VERSION 5.7 ;
BUSBITCHARS "[]" ;
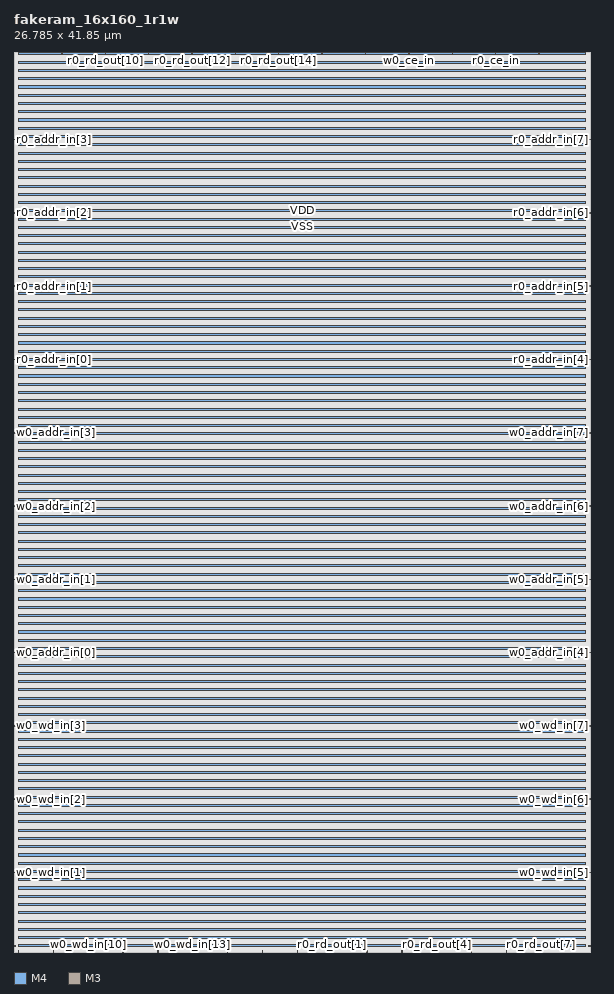
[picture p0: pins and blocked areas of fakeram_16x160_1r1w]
MACRO fakeram_16x160_1r1w
  FOREIGN fakeram_16x160_1r1w 0 0 ;
  SYMMETRY X Y R90 ;
  SIZE 26.785 BY 41.850 ;
  CLASS BLOCK ;
  PIN w0_wd_in[0]
    DIRECTION INPUT ;
    USE SIGNAL ;
    SHAPE ABUTMENT ;
    PORT
      LAYER M4 ;
      RECT 0.000 0.276 0.072 0.300 ;
    END
  END w0_wd_in[0]
  PIN w0_wd_in[1]
    DIRECTION INPUT ;
    USE SIGNAL ;
    SHAPE ABUTMENT ;
    PORT
      LAYER M4 ;
      RECT 0.000 3.684 0.072 3.708 ;
    END
  END w0_wd_in[1]
  PIN w0_wd_in[2]
    DIRECTION INPUT ;
    USE SIGNAL ;
    SHAPE ABUTMENT ;
    PORT
      LAYER M4 ;
      RECT 0.000 7.092 0.072 7.116 ;
    END
  END w0_wd_in[2]
  PIN w0_wd_in[3]
    DIRECTION INPUT ;
    USE SIGNAL ;
    SHAPE ABUTMENT ;
    PORT
      LAYER M4 ;
      RECT 0.000 10.500 0.072 10.524 ;
    END
  END w0_wd_in[3]
  PIN w0_wd_in[4]
    DIRECTION INPUT ;
    USE SIGNAL ;
    SHAPE ABUTMENT ;
    PORT
      LAYER M4 ;
      RECT 26.713 0.276 26.785 0.300 ;
    END
  END w0_wd_in[4]
  PIN w0_wd_in[5]
    DIRECTION INPUT ;
    USE SIGNAL ;
    SHAPE ABUTMENT ;
    PORT
      LAYER M4 ;
      RECT 26.713 3.684 26.785 3.708 ;
    END
  END w0_wd_in[5]
  PIN w0_wd_in[6]
    DIRECTION INPUT ;
    USE SIGNAL ;
    SHAPE ABUTMENT ;
    PORT
      LAYER M4 ;
      RECT 26.713 7.092 26.785 7.116 ;
    END
  END w0_wd_in[6]
  PIN w0_wd_in[7]
    DIRECTION INPUT ;
    USE SIGNAL ;
    SHAPE ABUTMENT ;
    PORT
      LAYER M4 ;
      RECT 26.713 10.500 26.785 10.524 ;
    END
  END w0_wd_in[7]
  PIN w0_wd_in[8]
    DIRECTION INPUT ;
    USE SIGNAL ;
    SHAPE ABUTMENT ;
    PORT
      LAYER M3 ;
      RECT 0.207 0.000 0.225 0.054 ;
    END
  END w0_wd_in[8]
  PIN w0_wd_in[9]
    DIRECTION INPUT ;
    USE SIGNAL ;
    SHAPE ABUTMENT ;
    PORT
      LAYER M3 ;
      RECT 1.827 0.000 1.845 0.054 ;
    END
  END w0_wd_in[9]
  PIN w0_wd_in[10]
    DIRECTION INPUT ;
    USE SIGNAL ;
    SHAPE ABUTMENT ;
    PORT
      LAYER M3 ;
      RECT 3.447 0.000 3.465 0.054 ;
    END
  END w0_wd_in[10]
  PIN w0_wd_in[11]
    DIRECTION INPUT ;
    USE SIGNAL ;
    SHAPE ABUTMENT ;
    PORT
      LAYER M3 ;
      RECT 5.067 0.000 5.085 0.054 ;
    END
  END w0_wd_in[11]
  PIN w0_wd_in[12]
    DIRECTION INPUT ;
    USE SIGNAL ;
    SHAPE ABUTMENT ;
    PORT
      LAYER M3 ;
      RECT 6.687 0.000 6.705 0.054 ;
    END
  END w0_wd_in[12]
  PIN w0_wd_in[13]
    DIRECTION INPUT ;
    USE SIGNAL ;
    SHAPE ABUTMENT ;
    PORT
      LAYER M3 ;
      RECT 8.307 0.000 8.325 0.054 ;
    END
  END w0_wd_in[13]
  PIN w0_wd_in[14]
    DIRECTION INPUT ;
    USE SIGNAL ;
    SHAPE ABUTMENT ;
    PORT
      LAYER M3 ;
      RECT 9.927 0.000 9.945 0.054 ;
    END
  END w0_wd_in[14]
  PIN w0_wd_in[15]
    DIRECTION INPUT ;
    USE SIGNAL ;
    SHAPE ABUTMENT ;
    PORT
      LAYER M3 ;
      RECT 11.547 0.000 11.565 0.054 ;
    END
  END w0_wd_in[15]
  PIN r0_rd_out[0]
    DIRECTION OUTPUT ;
    USE SIGNAL ;
    SHAPE ABUTMENT ;
    PORT
      LAYER M3 ;
      RECT 13.167 0.000 13.185 0.054 ;
    END
  END r0_rd_out[0]
  PIN r0_rd_out[1]
    DIRECTION OUTPUT ;
    USE SIGNAL ;
    SHAPE ABUTMENT ;
    PORT
      LAYER M3 ;
      RECT 14.787 0.000 14.805 0.054 ;
    END
  END r0_rd_out[1]
  PIN r0_rd_out[2]
    DIRECTION OUTPUT ;
    USE SIGNAL ;
    SHAPE ABUTMENT ;
    PORT
      LAYER M3 ;
      RECT 16.407 0.000 16.425 0.054 ;
    END
  END r0_rd_out[2]
  PIN r0_rd_out[3]
    DIRECTION OUTPUT ;
    USE SIGNAL ;
    SHAPE ABUTMENT ;
    PORT
      LAYER M3 ;
      RECT 18.027 0.000 18.045 0.054 ;
    END
  END r0_rd_out[3]
  PIN r0_rd_out[4]
    DIRECTION OUTPUT ;
    USE SIGNAL ;
    SHAPE ABUTMENT ;
    PORT
      LAYER M3 ;
      RECT 19.647 0.000 19.665 0.054 ;
    END
  END r0_rd_out[4]
  PIN r0_rd_out[5]
    DIRECTION OUTPUT ;
    USE SIGNAL ;
    SHAPE ABUTMENT ;
    PORT
      LAYER M3 ;
      RECT 21.267 0.000 21.285 0.054 ;
    END
  END r0_rd_out[5]
  PIN r0_rd_out[6]
    DIRECTION OUTPUT ;
    USE SIGNAL ;
    SHAPE ABUTMENT ;
    PORT
      LAYER M3 ;
      RECT 22.887 0.000 22.905 0.054 ;
    END
  END r0_rd_out[6]
  PIN r0_rd_out[7]
    DIRECTION OUTPUT ;
    USE SIGNAL ;
    SHAPE ABUTMENT ;
    PORT
      LAYER M3 ;
      RECT 24.507 0.000 24.525 0.054 ;
    END
  END r0_rd_out[7]
  PIN r0_rd_out[8]
    DIRECTION OUTPUT ;
    USE SIGNAL ;
    SHAPE ABUTMENT ;
    PORT
      LAYER M3 ;
      RECT 0.207 41.796 0.225 41.850 ;
    END
  END r0_rd_out[8]
  PIN r0_rd_out[9]
    DIRECTION OUTPUT ;
    USE SIGNAL ;
    SHAPE ABUTMENT ;
    PORT
      LAYER M3 ;
      RECT 2.223 41.796 2.241 41.850 ;
    END
  END r0_rd_out[9]
  PIN r0_rd_out[10]
    DIRECTION OUTPUT ;
    USE SIGNAL ;
    SHAPE ABUTMENT ;
    PORT
      LAYER M3 ;
      RECT 4.239 41.796 4.257 41.850 ;
    END
  END r0_rd_out[10]
  PIN r0_rd_out[11]
    DIRECTION OUTPUT ;
    USE SIGNAL ;
    SHAPE ABUTMENT ;
    PORT
      LAYER M3 ;
      RECT 6.255 41.796 6.273 41.850 ;
    END
  END r0_rd_out[11]
  PIN r0_rd_out[12]
    DIRECTION OUTPUT ;
    USE SIGNAL ;
    SHAPE ABUTMENT ;
    PORT
      LAYER M3 ;
      RECT 8.271 41.796 8.289 41.850 ;
    END
  END r0_rd_out[12]
  PIN r0_rd_out[13]
    DIRECTION OUTPUT ;
    USE SIGNAL ;
    SHAPE ABUTMENT ;
    PORT
      LAYER M3 ;
      RECT 10.287 41.796 10.305 41.850 ;
    END
  END r0_rd_out[13]
  PIN r0_rd_out[14]
    DIRECTION OUTPUT ;
    USE SIGNAL ;
    SHAPE ABUTMENT ;
    PORT
      LAYER M3 ;
      RECT 12.303 41.796 12.321 41.850 ;
    END
  END r0_rd_out[14]
  PIN r0_rd_out[15]
    DIRECTION OUTPUT ;
    USE SIGNAL ;
    SHAPE ABUTMENT ;
    PORT
      LAYER M3 ;
      RECT 14.319 41.796 14.337 41.850 ;
    END
  END r0_rd_out[15]
  PIN w0_addr_in[0]
    DIRECTION INPUT ;
    USE SIGNAL ;
    SHAPE ABUTMENT ;
    PORT
      LAYER M4 ;
      RECT 0.000 13.908 0.072 13.932 ;
    END
  END w0_addr_in[0]
  PIN w0_addr_in[1]
    DIRECTION INPUT ;
    USE SIGNAL ;
    SHAPE ABUTMENT ;
    PORT
      LAYER M4 ;
      RECT 0.000 17.316 0.072 17.340 ;
    END
  END w0_addr_in[1]
  PIN w0_addr_in[2]
    DIRECTION INPUT ;
    USE SIGNAL ;
    SHAPE ABUTMENT ;
    PORT
      LAYER M4 ;
      RECT 0.000 20.724 0.072 20.748 ;
    END
  END w0_addr_in[2]
  PIN w0_addr_in[3]
    DIRECTION INPUT ;
    USE SIGNAL ;
    SHAPE ABUTMENT ;
    PORT
      LAYER M4 ;
      RECT 0.000 24.132 0.072 24.156 ;
    END
  END w0_addr_in[3]
  PIN w0_addr_in[4]
    DIRECTION INPUT ;
    USE SIGNAL ;
    SHAPE ABUTMENT ;
    PORT
      LAYER M4 ;
      RECT 26.713 13.908 26.785 13.932 ;
    END
  END w0_addr_in[4]
  PIN w0_addr_in[5]
    DIRECTION INPUT ;
    USE SIGNAL ;
    SHAPE ABUTMENT ;
    PORT
      LAYER M4 ;
      RECT 26.713 17.316 26.785 17.340 ;
    END
  END w0_addr_in[5]
  PIN w0_addr_in[6]
    DIRECTION INPUT ;
    USE SIGNAL ;
    SHAPE ABUTMENT ;
    PORT
      LAYER M4 ;
      RECT 26.713 20.724 26.785 20.748 ;
    END
  END w0_addr_in[6]
  PIN w0_addr_in[7]
    DIRECTION INPUT ;
    USE SIGNAL ;
    SHAPE ABUTMENT ;
    PORT
      LAYER M4 ;
      RECT 26.713 24.132 26.785 24.156 ;
    END
  END w0_addr_in[7]
  PIN r0_addr_in[0]
    DIRECTION INPUT ;
    USE SIGNAL ;
    SHAPE ABUTMENT ;
    PORT
      LAYER M4 ;
      RECT 0.000 27.540 0.072 27.564 ;
    END
  END r0_addr_in[0]
  PIN r0_addr_in[1]
    DIRECTION INPUT ;
    USE SIGNAL ;
    SHAPE ABUTMENT ;
    PORT
      LAYER M4 ;
      RECT 0.000 30.948 0.072 30.972 ;
    END
  END r0_addr_in[1]
  PIN r0_addr_in[2]
    DIRECTION INPUT ;
    USE SIGNAL ;
    SHAPE ABUTMENT ;
    PORT
      LAYER M4 ;
      RECT 0.000 34.356 0.072 34.380 ;
    END
  END r0_addr_in[2]
  PIN r0_addr_in[3]
    DIRECTION INPUT ;
    USE SIGNAL ;
    SHAPE ABUTMENT ;
    PORT
      LAYER M4 ;
      RECT 0.000 37.764 0.072 37.788 ;
    END
  END r0_addr_in[3]
  PIN r0_addr_in[4]
    DIRECTION INPUT ;
    USE SIGNAL ;
    SHAPE ABUTMENT ;
    PORT
      LAYER M4 ;
      RECT 26.713 27.540 26.785 27.564 ;
    END
  END r0_addr_in[4]
  PIN r0_addr_in[5]
    DIRECTION INPUT ;
    USE SIGNAL ;
    SHAPE ABUTMENT ;
    PORT
      LAYER M4 ;
      RECT 26.713 30.948 26.785 30.972 ;
    END
  END r0_addr_in[5]
  PIN r0_addr_in[6]
    DIRECTION INPUT ;
    USE SIGNAL ;
    SHAPE ABUTMENT ;
    PORT
      LAYER M4 ;
      RECT 26.713 34.356 26.785 34.380 ;
    END
  END r0_addr_in[6]
  PIN r0_addr_in[7]
    DIRECTION INPUT ;
    USE SIGNAL ;
    SHAPE ABUTMENT ;
    PORT
      LAYER M4 ;
      RECT 26.713 37.764 26.785 37.788 ;
    END
  END r0_addr_in[7]
  PIN w0_we_in
    DIRECTION INPUT ;
    USE SIGNAL ;
    SHAPE ABUTMENT ;
    PORT
      LAYER M3 ;
      RECT 16.335 41.796 16.353 41.850 ;
    END
  END w0_we_in
  PIN w0_ce_in
    DIRECTION INPUT ;
    USE SIGNAL ;
    SHAPE ABUTMENT ;
    PORT
      LAYER M3 ;
      RECT 18.351 41.796 18.369 41.850 ;
    END
  END w0_ce_in
  PIN w0_clk
    DIRECTION INPUT ;
    USE SIGNAL ;
    SHAPE ABUTMENT ;
    PORT
      LAYER M3 ;
      RECT 20.367 41.796 20.385 41.850 ;
    END
  END w0_clk
  PIN r0_ce_in
    DIRECTION INPUT ;
    USE SIGNAL ;
    SHAPE ABUTMENT ;
    PORT
      LAYER M3 ;
      RECT 22.383 41.796 22.401 41.850 ;
    END
  END r0_ce_in
  PIN r0_clk
    DIRECTION INPUT ;
    USE SIGNAL ;
    SHAPE ABUTMENT ;
    PORT
      LAYER M3 ;
      RECT 24.399 41.796 24.417 41.850 ;
    END
  END r0_clk
  PIN VSS
    DIRECTION INOUT ;
    USE GROUND ;
    PORT
      LAYER M4 ;
      RECT 0.216 0.240 26.569 0.336 ;
      RECT 0.216 1.008 26.569 1.104 ;
      RECT 0.216 1.776 26.569 1.872 ;
      RECT 0.216 2.544 26.569 2.640 ;
      RECT 0.216 3.312 26.569 3.408 ;
      RECT 0.216 4.080 26.569 4.176 ;
      RECT 0.216 4.848 26.569 4.944 ;
      RECT 0.216 5.616 26.569 5.712 ;
      RECT 0.216 6.384 26.569 6.480 ;
      RECT 0.216 7.152 26.569 7.248 ;
      RECT 0.216 7.920 26.569 8.016 ;
      RECT 0.216 8.688 26.569 8.784 ;
      RECT 0.216 9.456 26.569 9.552 ;
      RECT 0.216 10.224 26.569 10.320 ;
      RECT 0.216 10.992 26.569 11.088 ;
      RECT 0.216 11.760 26.569 11.856 ;
      RECT 0.216 12.528 26.569 12.624 ;
      RECT 0.216 13.296 26.569 13.392 ;
      RECT 0.216 14.064 26.569 14.160 ;
      RECT 0.216 14.832 26.569 14.928 ;
      RECT 0.216 15.600 26.569 15.696 ;
      RECT 0.216 16.368 26.569 16.464 ;
      RECT 0.216 17.136 26.569 17.232 ;
      RECT 0.216 17.904 26.569 18.000 ;
      RECT 0.216 18.672 26.569 18.768 ;
      RECT 0.216 19.440 26.569 19.536 ;
      RECT 0.216 20.208 26.569 20.304 ;
      RECT 0.216 20.976 26.569 21.072 ;
      RECT 0.216 21.744 26.569 21.840 ;
      RECT 0.216 22.512 26.569 22.608 ;
      RECT 0.216 23.280 26.569 23.376 ;
      RECT 0.216 24.048 26.569 24.144 ;
      RECT 0.216 24.816 26.569 24.912 ;
      RECT 0.216 25.584 26.569 25.680 ;
      RECT 0.216 26.352 26.569 26.448 ;
      RECT 0.216 27.120 26.569 27.216 ;
      RECT 0.216 27.888 26.569 27.984 ;
      RECT 0.216 28.656 26.569 28.752 ;
      RECT 0.216 29.424 26.569 29.520 ;
      RECT 0.216 30.192 26.569 30.288 ;
      RECT 0.216 30.960 26.569 31.056 ;
      RECT 0.216 31.728 26.569 31.824 ;
      RECT 0.216 32.496 26.569 32.592 ;
      RECT 0.216 33.264 26.569 33.360 ;
      RECT 0.216 34.032 26.569 34.128 ;
      RECT 0.216 34.800 26.569 34.896 ;
      RECT 0.216 35.568 26.569 35.664 ;
      RECT 0.216 36.336 26.569 36.432 ;
      RECT 0.216 37.104 26.569 37.200 ;
      RECT 0.216 37.872 26.569 37.968 ;
      RECT 0.216 38.640 26.569 38.736 ;
      RECT 0.216 39.408 26.569 39.504 ;
      RECT 0.216 40.176 26.569 40.272 ;
      RECT 0.216 40.944 26.569 41.040 ;
      RECT 0.216 41.712 26.569 41.808 ;
    END
  END VSS
  PIN VDD
    DIRECTION INOUT ;
    USE POWER ;
    PORT
      LAYER M4 ;
      RECT 0.216 0.624 26.569 0.720 ;
      RECT 0.216 1.392 26.569 1.488 ;
      RECT 0.216 2.160 26.569 2.256 ;
      RECT 0.216 2.928 26.569 3.024 ;
      RECT 0.216 3.696 26.569 3.792 ;
      RECT 0.216 4.464 26.569 4.560 ;
      RECT 0.216 5.232 26.569 5.328 ;
      RECT 0.216 6.000 26.569 6.096 ;
      RECT 0.216 6.768 26.569 6.864 ;
      RECT 0.216 7.536 26.569 7.632 ;
      RECT 0.216 8.304 26.569 8.400 ;
      RECT 0.216 9.072 26.569 9.168 ;
      RECT 0.216 9.840 26.569 9.936 ;
      RECT 0.216 10.608 26.569 10.704 ;
      RECT 0.216 11.376 26.569 11.472 ;
      RECT 0.216 12.144 26.569 12.240 ;
      RECT 0.216 12.912 26.569 13.008 ;
      RECT 0.216 13.680 26.569 13.776 ;
      RECT 0.216 14.448 26.569 14.544 ;
      RECT 0.216 15.216 26.569 15.312 ;
      RECT 0.216 15.984 26.569 16.080 ;
      RECT 0.216 16.752 26.569 16.848 ;
      RECT 0.216 17.520 26.569 17.616 ;
      RECT 0.216 18.288 26.569 18.384 ;
      RECT 0.216 19.056 26.569 19.152 ;
      RECT 0.216 19.824 26.569 19.920 ;
      RECT 0.216 20.592 26.569 20.688 ;
      RECT 0.216 21.360 26.569 21.456 ;
      RECT 0.216 22.128 26.569 22.224 ;
      RECT 0.216 22.896 26.569 22.992 ;
      RECT 0.216 23.664 26.569 23.760 ;
      RECT 0.216 24.432 26.569 24.528 ;
      RECT 0.216 25.200 26.569 25.296 ;
      RECT 0.216 25.968 26.569 26.064 ;
      RECT 0.216 26.736 26.569 26.832 ;
      RECT 0.216 27.504 26.569 27.600 ;
      RECT 0.216 28.272 26.569 28.368 ;
      RECT 0.216 29.040 26.569 29.136 ;
      RECT 0.216 29.808 26.569 29.904 ;
      RECT 0.216 30.576 26.569 30.672 ;
      RECT 0.216 31.344 26.569 31.440 ;
      RECT 0.216 32.112 26.569 32.208 ;
      RECT 0.216 32.880 26.569 32.976 ;
      RECT 0.216 33.648 26.569 33.744 ;
      RECT 0.216 34.416 26.569 34.512 ;
      RECT 0.216 35.184 26.569 35.280 ;
      RECT 0.216 35.952 26.569 36.048 ;
      RECT 0.216 36.720 26.569 36.816 ;
      RECT 0.216 37.488 26.569 37.584 ;
      RECT 0.216 38.256 26.569 38.352 ;
      RECT 0.216 39.024 26.569 39.120 ;
      RECT 0.216 39.792 26.569 39.888 ;
      RECT 0.216 40.560 26.569 40.656 ;
      RECT 0.216 41.328 26.569 41.424 ;
    END
  END VDD
  OBS
    LAYER M1 ;
    RECT 0 0 26.785 41.850 ;
    LAYER M2 ;
    RECT 0 0 26.785 41.850 ;
    LAYER M3 ;
    RECT 0 0 26.785 41.850 ;
    LAYER M4 ;
    RECT 0 0 26.785 41.850 ;
  END
END fakeram_16x160_1r1w

END LIBRARY
